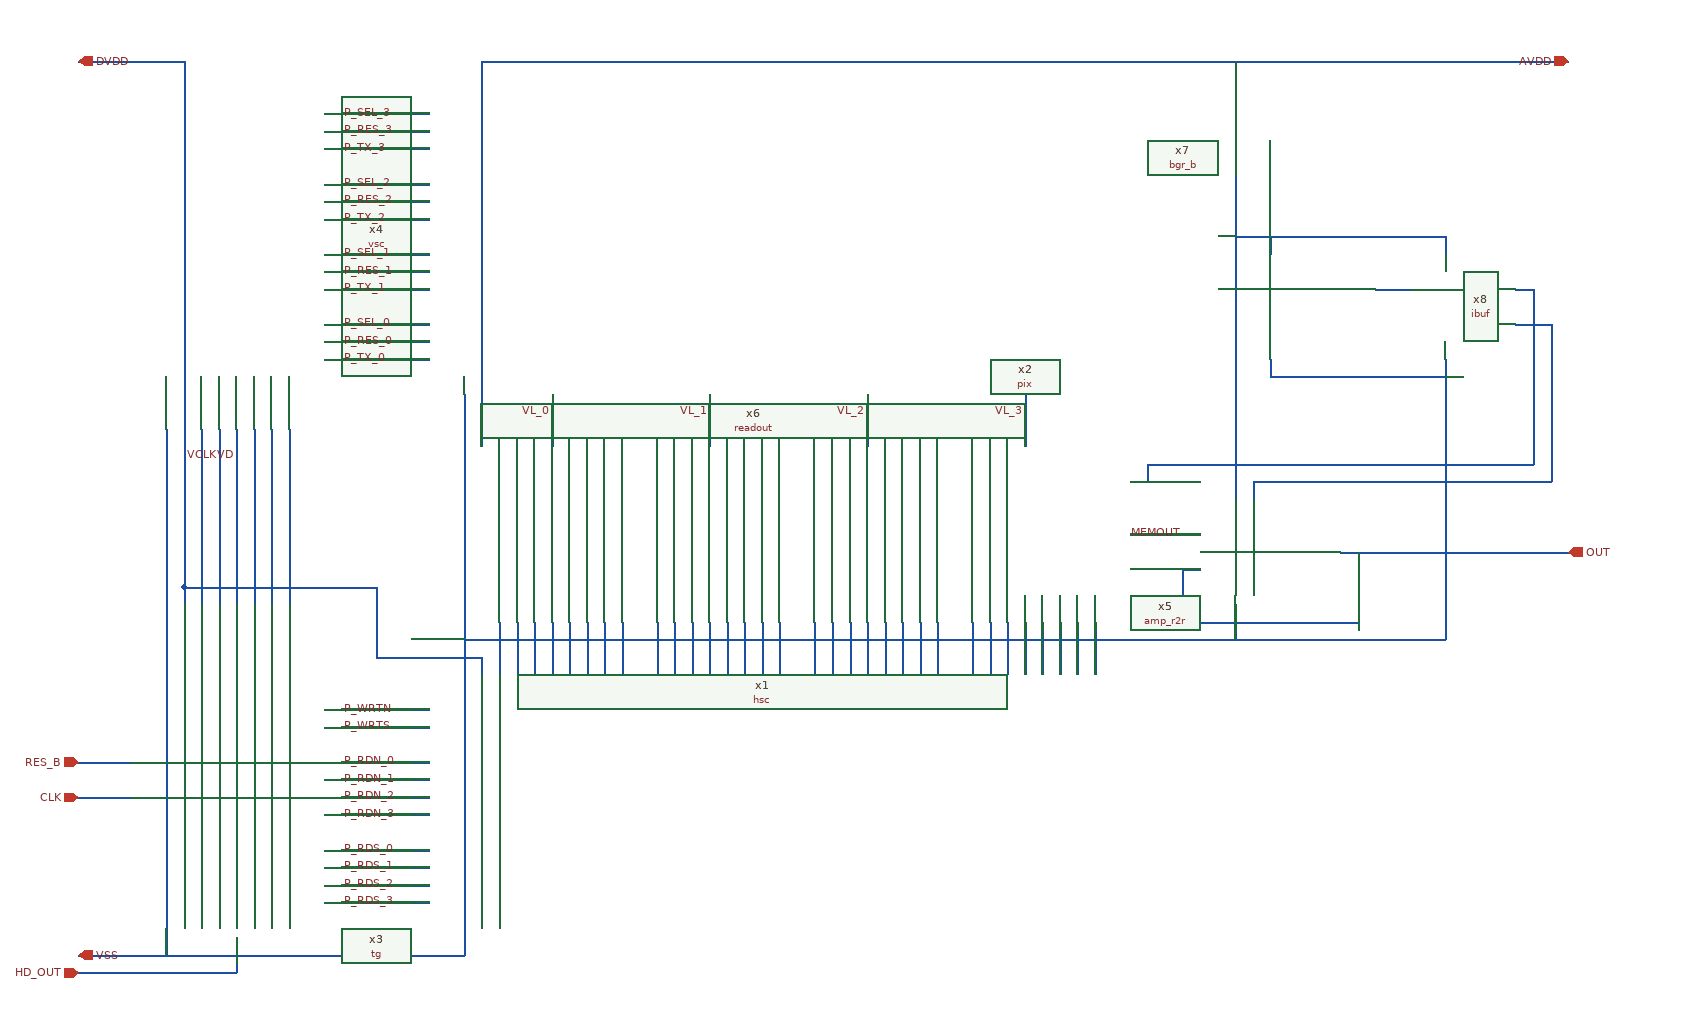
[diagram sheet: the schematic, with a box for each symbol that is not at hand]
v {xschem version=3.4.8RC file_version=1.2}
G {}
K {}
V {}
S {}
E {}
N 340 -640 340 -440 {lab=#net1}
N 360 -640 360 -440 {lab=VCLK}
N 380 -640 380 -440 {lab=VD}
N 400 -640 400 -440 {lab=#net2}
N 420 -640 420 -440 {lab=#net3}
N 440 -640 440 -440 {lab=#net4}
N 480 -320 600 -320 {lab=P_WRTN}
N 480 -300 600 -300 {lab=P_WRTS}
N 480 -260 600 -260 {lab=P_RDN_0}
N 480 -240 600 -240 {lab=P_RDN_1}
N 480 -220 600 -220 {lab=P_RDN_2}
N 480 -200 600 -200 {lab=P_RDN_3}
N 480 -160 600 -160 {lab=P_RDS_0}
N 480 -140 600 -140 {lab=P_RDS_1}
N 480 -120 600 -120 {lab=P_RDS_2}
N 480 -100 600 -100 {lab=P_RDS_3}
N 680 -420 680 -360 {lab=#net5}
N 700 -420 700 -360 {lab=#net6}
N 720 -420 720 -360 {lab=#net7}
N 740 -420 740 -360 {lab=#net8}
N 760 -420 760 -360 {lab=#net9}
N 780 -420 780 -360 {lab=#net10}
N 800 -420 800 -360 {lab=#net11}
N 820 -420 820 -360 {lab=#net12}
N 860 -420 860 -360 {lab=#net13}
N 880 -420 880 -360 {lab=#net14}
N 900 -420 900 -360 {lab=#net15}
N 920 -420 920 -360 {lab=#net16}
N 940 -420 940 -360 {lab=#net17}
N 960 -420 960 -360 {lab=#net18}
N 980 -420 980 -360 {lab=#net19}
N 1000 -420 1000 -360 {lab=#net20}
N 1040 -420 1040 -360 {lab=#net21}
N 1060 -420 1060 -360 {lab=#net22}
N 1080 -420 1080 -360 {lab=#net23}
N 1100 -420 1100 -360 {lab=#net24}
N 1120 -420 1120 -360 {lab=#net25}
N 1140 -420 1140 -360 {lab=#net26}
N 1160 -420 1160 -360 {lab=#net27}
N 1180 -420 1180 -360 {lab=#net28}
N 1220 -420 1220 -360 {lab=#net29}
N 1240 -420 1240 -360 {lab=#net30}
N 1260 -420 1260 -360 {lab=#net31}
N 1280 -420 1280 -360 {lab=#net32}
N 1300 -420 1300 -360 {lab=#net33}
N 1320 -420 1320 -360 {lab=#net34}
N 1340 -420 1340 -360 {lab=#net35}
N 1360 -420 1360 -360 {lab=#net36}
N 1280 -680 1280 -620 {lab=VL_3}
N 1100 -680 1100 -620 {lab=VL_2}
N 920 -680 920 -620 {lab=VL_1}
N 740 -680 740 -620 {lab=VL_0}
N 660 -1060 660 -620 {lab=AVDD}
N 640 -680 640 -40 {lab=VSS}
N 640 -400 1760 -400 {lab=VSS}
N 1520 -440 1520 -400 {lab=VSS}
N 660 -1060 1900 -1060 {lab=AVDD}
N 1640 -500 1900 -500 {lab=OUT}
N 1520 -1060 1520 -560 {lab=AVDD}
N 480 -720 600 -720 {lab=P_TX_0}
N 480 -740 600 -740 {lab=P_RES_0}
N 480 -760 600 -760 {lab=P_SEL_0}
N 480 -800 600 -800 {lab=P_TX_1}
N 480 -820 600 -820 {lab=P_RES_1}
N 480 -840 600 -840 {lab=P_SEL_1}
N 480 -880 600 -880 {lab=P_TX_2}
N 480 -900 600 -900 {lab=P_RES_2}
N 480 -920 600 -920 {lab=P_SEL_2}
N 480 -960 600 -960 {lab=P_TX_3}
N 480 -980 600 -980 {lab=P_RES_3}
N 480 -1000 600 -1000 {lab=P_SEL_3}
N 300 -640 300 -40 {lab=VSS}
N 320 -460 540 -460 {lab=#net37}
N 200 -40 640 -40 {lab=VSS}
N 380 -60 380 -20 {lab=HD_OUT}
N 200 -20 380 -20 {lab=HD_OUT}
N 200 -220 260 -220 {lab=CLK}
N 200 -260 260 -260 {lab=RES_B}
N 1400 -520 1480 -520 {lab=MEMOUT}
N 1460 -480 1480 -480 {lab=OUT}
N 1460 -480 1460 -420 {lab=OUT}
N 1460 -420 1660 -420 {lab=OUT}
N 1660 -500 1660 -420 {lab=OUT}
N 1520 -860 1760 -860 {lab=AVDD}
N 1760 -860 1760 -840 {lab=AVDD}
N 1560 -860 1560 -840 {lab=AVDD}
N 1680 -800 1720 -800 {lab=#net38}
N 1760 -720 1760 -400 {lab=VSS}
N 1560 -700 1760 -700 {lab=VSS}
N 1560 -720 1560 -700 {lab=VSS}
N 1400 -580 1420 -580 {lab=#net39}
N 1420 -600 1420 -580 {lab=#net39}
N 1420 -600 1860 -600 {lab=#net39}
N 1540 -580 1540 -560 {lab=#net40}
N 1540 -580 1880 -580 {lab=#net40}
N 1860 -800 1860 -600 {lab=#net39}
N 1840 -800 1860 -800 {lab=#net39}
N 1840 -760 1880 -760 {lab=#net40}
N 1880 -760 1880 -580 {lab=#net40}
N 320 -460 320 -440 {lab=#net37}
N 540 -460 540 -380 {lab=#net37}
N 540 -380 660 -380 {lab=#net37}
N 660 -380 660 -360 {lab=#net37}
N 320 -1060 320 -460 {lab=#net37}
N 200 -1060 320 -1060 {lab=DVDD}
C {2026_imager/hsc.sym} 1000 -210 0 0 {name=x1}
C {2026_imager/pix.sym} 1040 -860 0 0 {name=x2}
C {2026_imager/tg.sym} 380 -240 0 0 {name=x3}
C {2026_imager/vsc.sym} 380 -840 0 0 {name=x4}
C {2026_imager/amp_r2r.sym} 1560 -500 0 0 {name=x5}
C {2026_imager/readout.sym} 1000 -520 0 0 {name=x6}
C {devices/iopin.sym} 200 -40 0 1 {name=p1 lab=VSS}
C {devices/iopin.sym} 200 -1060 0 1 {name=p2 lab=DVDD}
C {devices/iopin.sym} 1900 -1060 0 0 {name=p3 lab=AVDD}
C {devices/ipin.sym} 200 -220 0 0 {name=p4 lab=CLK}
C {devices/ipin.sym} 200 -260 0 0 {name=p5 lab=RES_B}
C {devices/opin.sym} 200 -20 0 1 {name=p6 lab=HD_OUT}
C {devices/opin.sym} 1900 -500 0 0 {name=p7 lab=OUT}
C {2026_book/bgr_b.sym} 1600 -780 0 0 {name=x7}
C {2026_book/ibuf.sym} 1780 -780 0 0 {name=x8}
C {devices/lab_wire.sym} 1460 -520 0 0 {name=p8 sig_type=std_logic lab=MEMOUT}
C {devices/lab_wire.sym} 500 -260 0 1 {name=p9 sig_type=std_logic lab=P_RDN_0}
C {devices/lab_wire.sym} 500 -240 0 1 {name=p10 sig_type=std_logic lab=P_RDN_1}
C {devices/lab_wire.sym} 500 -220 0 1 {name=p11 sig_type=std_logic lab=P_RDN_2}
C {devices/lab_wire.sym} 500 -200 0 1 {name=p12 sig_type=std_logic lab=P_RDN_3}
C {devices/lab_wire.sym} 500 -160 0 1 {name=p13 sig_type=std_logic lab=P_RDS_0}
C {devices/lab_wire.sym} 500 -140 0 1 {name=p14 sig_type=std_logic lab=P_RDS_1}
C {devices/lab_wire.sym} 500 -120 0 1 {name=p15 sig_type=std_logic lab=P_RDS_2}
C {devices/lab_wire.sym} 500 -100 0 1 {name=p16 sig_type=std_logic lab=P_RDS_3}
C {devices/lab_wire.sym} 500 -320 0 1 {name=p17 sig_type=std_logic lab=P_WRTN}
C {devices/lab_wire.sym} 500 -300 0 1 {name=p18 sig_type=std_logic lab=P_WRTS}
C {devices/lab_wire.sym} 500 -720 0 1 {name=p19 sig_type=std_logic lab=P_TX_0}
C {devices/lab_wire.sym} 500 -740 0 1 {name=p20 sig_type=std_logic lab=P_RES_0}
C {devices/lab_wire.sym} 500 -760 0 1 {name=p21 sig_type=std_logic lab=P_SEL_0}
C {devices/lab_wire.sym} 500 -800 0 1 {name=p22 sig_type=std_logic lab=P_TX_1}
C {devices/lab_wire.sym} 500 -820 0 1 {name=p23 sig_type=std_logic lab=P_RES_1}
C {devices/lab_wire.sym} 500 -840 0 1 {name=p24 sig_type=std_logic lab=P_SEL_1}
C {devices/lab_wire.sym} 500 -880 0 1 {name=p25 sig_type=std_logic lab=P_TX_2}
C {devices/lab_wire.sym} 500 -900 0 1 {name=p26 sig_type=std_logic lab=P_RES_2}
C {devices/lab_wire.sym} 500 -920 0 1 {name=p27 sig_type=std_logic lab=P_SEL_2}
C {devices/lab_wire.sym} 500 -960 0 1 {name=p28 sig_type=std_logic lab=P_TX_3}
C {devices/lab_wire.sym} 500 -980 0 1 {name=p29 sig_type=std_logic lab=P_RES_3}
C {devices/lab_wire.sym} 500 -1000 0 1 {name=p30 sig_type=std_logic lab=P_SEL_3}
C {devices/lab_wire.sym} 740 -660 3 0 {name=p31 sig_type=std_logic lab=VL_0}
C {devices/lab_wire.sym} 920 -660 3 0 {name=p32 sig_type=std_logic lab=VL_1}
C {devices/lab_wire.sym} 1100 -660 3 0 {name=p33 sig_type=std_logic lab=VL_2}
C {devices/lab_wire.sym} 1280 -660 3 0 {name=p34 sig_type=std_logic lab=VL_3}
C {devices/lab_wire.sym} 380 -610 3 0 {name=p35 sig_type=std_logic lab=VD}
C {devices/lab_wire.sym} 360 -610 3 0 {name=p36 sig_type=std_logic lab=VCLK}
